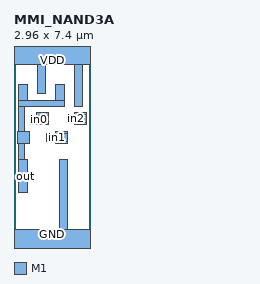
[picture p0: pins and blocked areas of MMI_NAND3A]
MACRO MMI_NAND3A
	CLASS CORE ;
	FOREIGN MMI_NAND3A 0 0 ;
	SIZE 2.96 BY 7.4 ;
	SYMMETRY X Y ;
	SITE CORE1 ;
	PIN out
		DIRECTION output ;
		USE SIGNAL ;
		PORT
			LAYER M1 ;
			RECT 0.18 5.515 0.52 6.125 ;
			LAYER M1 ;
			RECT 1.62 5.515 1.96 6.125 ;
			LAYER M1 ;
			RECT 0.18 5.285 1.96 5.515 ;
			LAYER M1 ;
			RECT 0.18 4.295 0.41 5.285 ;
			LAYER M1 ;
			RECT 0.145 3.845 0.595 4.295 ;
			LAYER M1 ;
			RECT 0.18 3.21 0.41 3.845 ;
			LAYER M1 ;
			RECT 0.18 1.91 0.52 3.21 ;
		END
		AntennaDiffArea 1.6008 ;
	END out
	PIN in1
		DIRECTION input ;
		USE SIGNAL ;
		PORT
			LAYER M1 ;
			RECT 1.625 4.24 2.075 4.295 ;
			LAYER M1 ;
			RECT 1.285 3.9 2.075 4.24 ;
			LAYER M1 ;
			RECT 1.625 3.845 2.075 3.9 ;
		END
		AntennaGateArea 0.414 ;
	END in1
	PIN GND
		DIRECTION inout ;
		USE GROUND ;
		PORT
			LAYER M1 ;
			RECT 1.76 0.5 2.1 3.21 ;
			LAYER M1 ;
			RECT 0 -0.5 2.96 0.5 ;
		END
	END GND
	PIN in2
		DIRECTION input ;
		USE SIGNAL ;
		PORT
			LAYER M1 ;
			RECT 2.365 4.975 2.815 5.035 ;
			LAYER M1 ;
			RECT 2.035 4.635 2.815 4.975 ;
			LAYER M1 ;
			RECT 2.365 4.585 2.815 4.635 ;
		END
		AntennaGateArea 0.414 ;
	END in2
	PIN VDD
		DIRECTION inout ;
		USE POWER ;
		PORT
			LAYER M1 ;
			RECT 0 6.9 2.96 7.9 ;
			LAYER M1 ;
			RECT 0.9 5.785 1.24 6.9 ;
			LAYER M1 ;
			RECT 2.34 5.285 2.68 6.9 ;
		END
	END VDD
	PIN in0
		DIRECTION input ;
		USE SIGNAL ;
		PORT
			LAYER M1 ;
			RECT 0.885 4.93 1.335 5.035 ;
			LAYER M1 ;
			RECT 0.64 4.59 1.335 4.93 ;
			LAYER M1 ;
			RECT 0.885 4.585 1.335 4.59 ;
		END
		AntennaGateArea 0.414 ;
	END in0
	OBS
	END
END MMI_NAND3A
